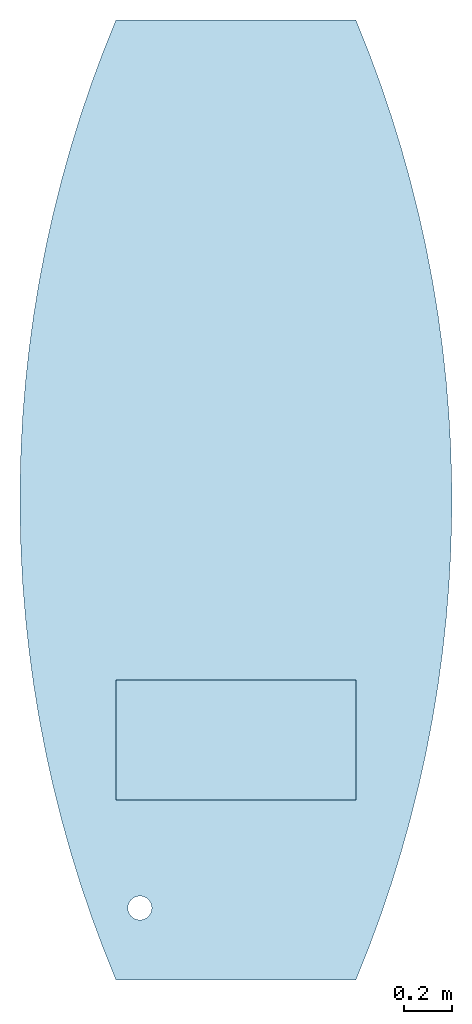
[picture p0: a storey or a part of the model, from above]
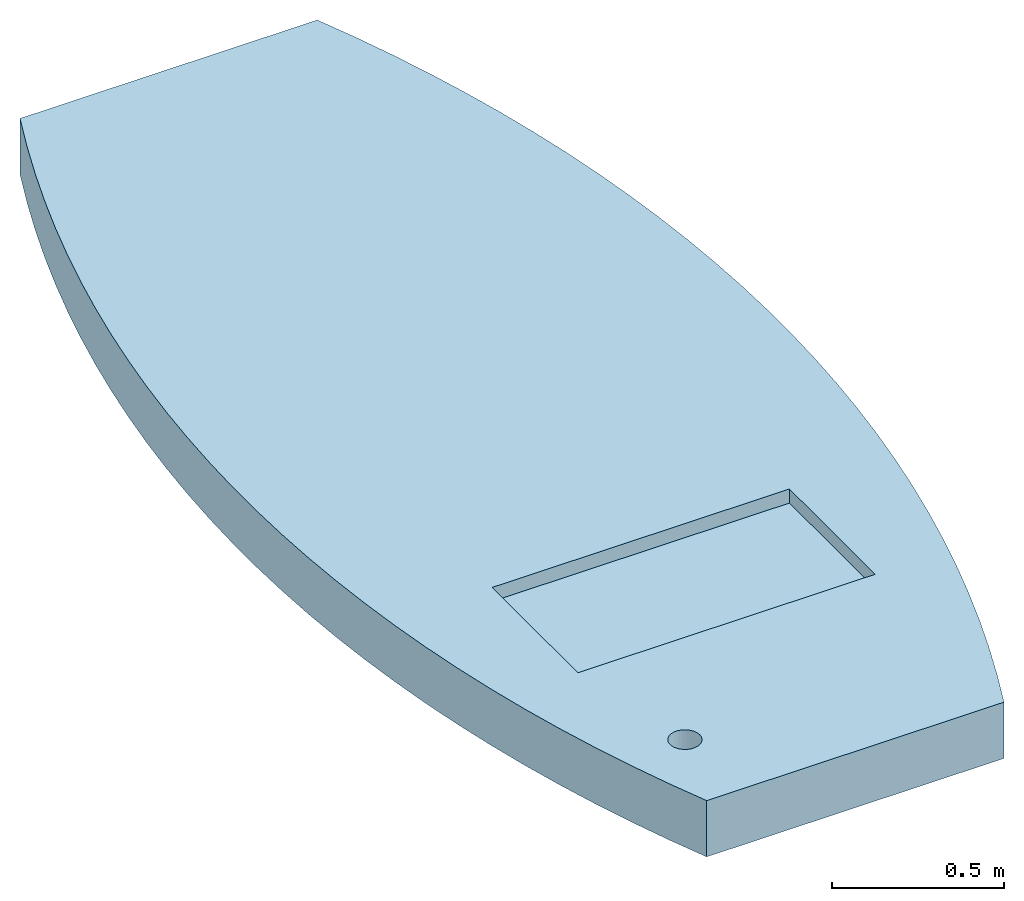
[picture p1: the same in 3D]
Properties of the parts of a building model (IFC4X3_ADD2)

# File
Description: ViewDefinition [DesignTransferView_V1]
File name: slab-openings.ifc
Time: 2016-02-04T08:47:55
Author: redacted
Organization: redacted
Written by: redacted
Made in: redacted
Comment: name
Comment: time_stamp
Comment: author
Comment: organization
Comment: preprocessor_version
Comment: originating_system
Comment: authorization
Comment: general entities required for all IFC data sets, defining the context for the exchange
Comment: defines the default building (as required as the minimum spatial element)

# IfcOpeningElement (2)
In: IfcBuilding
Name
Opening
Recess | PredefinedType: RECESS

# IfcSlab
In: IfcBuilding
Material: Concrete 200 mm

# IfcSlabType, no part of this type: 200mm Concrete
PredefinedType: FLOOR; Material: Concrete 200 mm
